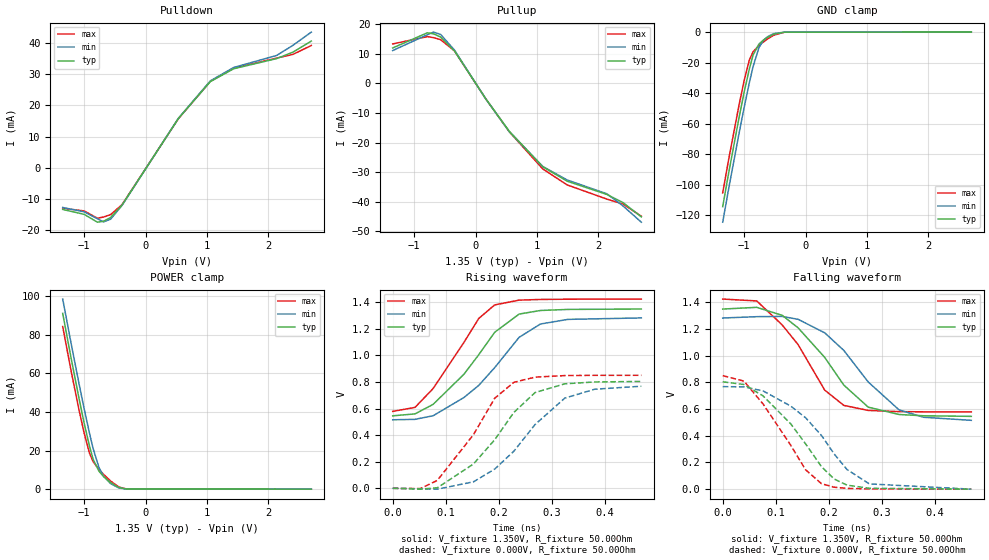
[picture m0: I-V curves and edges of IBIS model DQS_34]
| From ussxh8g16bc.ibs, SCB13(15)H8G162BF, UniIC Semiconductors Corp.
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| MODEL DQS_34 (34 Ohm Data Strobe I/O with no ODT, 800-2133Mbps)
[Model]   DQS_34
Model_type   I/O
Vinl = 545.000mV
Vinh = 805.000mV
Vmeas = 675.000mV
Vref = 675.000mV
Cref = 0.0pF
Rref = 25.000Ohm
|   typ   min   max
|C_comp   1.050pF   1.000pF   1.100pF
C_comp_pullup   0.5250pF   0.5000pF   0.5500pF
C_comp_pulldown   0.5250pF   0.5000pF   0.5500pF
[Model Spec]
| Input threshold voltage corners
Vinl   0.5450V   0.5115V   0.5825V
Vinh   0.8050V   0.7715V   0.8425V
| Measurement voltage corners
Vmeas   0.6750V   0.6415V   0.7125V
| Timing spec test load voltage corners
Vref   0.6750V   0.6415V   0.7125V
| Dynamic Overshoot Parameters from DDR3L Specification
|D_overshoot_ampl_h   0.40   NA   NA
|D_overshoot_ampl_l   0.40   NA   NA
|D_overshoot_area_h   0.11n   NA   NA
|D_overshoot_area_l   0.11n   NA   NA
[Receiver Thresholds]
|Vth   =  0.675V
|Vth_min  =  0.6615V
|Vth_max  =  0.6885V
|Vinh_ac  =  0.130V
|Vinh_dc  =  0.090V
|Vinl_ac  = -0.130V
|Vinl_dc  = -0.090V
|Tslew_ac =  5.000ns |Not specified, so set to high value
|Threshold_sensitivity = 0.50
|Reference_supply Pullup_ref
|NOTE: If using the IBISCHK 4.2.1 or older parser, Differential receiver
|threshold parameters must be commented out because the parser generates
|errors for multiple differential models.
Vcross_low   = 0.545V
Vcross_high  = 0.805V
Vdiff_ac   = 260mV
Vdiff_dc   = 180mV
Tdiffslew_ac = 10.000ns |Not specified, so set to high value
[Voltage Range]   1.3500V   1.2830V   1.4250V
[Pullup Reference]   1.3500V   1.2830V   1.4250V
| Junction Temperature (Ambient temp is 40C typ, 85C min, 0C max)
[Temperature Range]   45.0   90.0   0.0
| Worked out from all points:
|   slope of the pulldown table from 0 to 0.203 V, typ, clamps not added: 32.6 ohm
|   slope of the pullup table from 0 to 0.203 V, typ, clamps not added: 32.2 ohm
|   GND clamp passes 1 mA (typ) near -0.49 V on its own axis
|   POWER clamp passes 1 mA (typ) near -0.45 V on its own axis
|   falling waveform, V_fixture 1.350V, R_fixture 50.00Ohm: 20-80 % time 96.1ps typ, 99.3ps min, 84.6ps max; typ from 1.35 V to 0.546 V
|   rising waveform, V_fixture 1.350V, R_fixture 50.00Ohm: 20-80 % time 98.7ps typ, 106ps min, 82.4ps max; typ from 0.546 V to 1.35 V
|   rising waveform, V_fixture 0.000V, R_fixture 50.00Ohm: 20-80 % time 97.4ps typ, 105ps min, 83.3ps max; typ from 0 V to 0.805 V
|   falling waveform, V_fixture 0.000V, R_fixture 50.00Ohm: 20-80 % time 96.8ps typ, 102ps min, 82.8ps max; typ from 0.805 V to 0 V
[Pulldown]
|   Voltage   I(typ)   I(min)   I(max)
-1.35V    -13.34mA   -12.72mA   -12.97mA
-1V       -14.92mA   -14.12mA   -13.82mA
-785mV    -17.43mA   -16.34mA   -16.16mA
-685mV    -17.14mA   -17.33mA   -15.78mA
-570mV    -15.93mA   -16.47mA   -15mA
-385mV    -11.98mA   -12.09mA   -11.84mA
535mV     15.8mA     15.87mA    15.74mA
1.055V    27.62mA    27.85mA    27.66mA
1.435V    31.72mA    32.13mA    31.95mA
2.135V    34.98mA    35.99mA    35.14mA
2.4V      37.04mA    39.22mA    36.32mA
2.7V      40.59mA    43.47mA    39.18mA
[GND Clamp]
|   Voltage   I(typ)   I(min)   I(max)
-1.35V    -114.4mA   -124.6mA   -105.4mA
-1.25V    -91.71mA   -102mA     -82.85mA
-1.085V   -56.31mA   -66.65mA   -48.04mA
-1V       -39.18mA   -49.29mA   -31.62mA
-915mV    -23.97mA   -32.98mA   -18.22mA
-855mV    -15.04mA   -22.61mA   -12.89mA
-760mV    -7.865mA   -10.21mA   -8.802mA
-685mV    -5.148mA   -5.368mA   -6.421mA
-620mV    -3.44mA    -3.073mA   -4.512mA
-520mV    -1.403mA   -994uA     -2.069mA
-345mV    -90.02uA   -50.12uA   -72.43uA
2.7V      0A         0A         0A
[Pullup]
|   Voltage   I(typ)   I(min)   I(max)
-1.35V    12.01mA    11.13mA    13.37mA
-785mV    17.15mA    16.5mA     15.85mA
-685mV    16.79mA    17.38mA    15.5mA
-570mV    15.71mA    16.6mA     14.82mA
-345mV    11.06mA    11.33mA    11.04mA
165mV     -5.155mA   -5.209mA   -5.17mA
550mV     -16.21mA   -16.33mA   -16.37mA
1.095V    -28.19mA   -28.08mA   -28.92mA
1.49V     -33.05mA   -32.64mA   -34.31mA
2.14V     -37.57mA   -37.35mA   -39.14mA
2.4V      -40.28mA   -41.41mA   -40.77mA
2.7V      -45.13mA   -46.94mA   -44.93mA
[POWER Clamp]
|   Voltage   I(typ)   I(min)   I(max)
-1.35V    91.15mA    98.58mA    84.31mA
-1.21V    67.43mA    75.08mA    60.81mA
-1.085V   47.16mA    54.84mA    41.22mA
-1V       34.13mA    41.63mA    28.99mA
-915mV    22.48mA    29.16mA    18.77mA
-855mV    15.54mA    21.16mA    14.29mA
-760mV    9.343mA    11.27mA    10.24mA
-685mV    6.542mA    6.798mA    7.711mA
-570mV    3.396mA    2.887mA    4.217mA
-435mV    857.8uA    628.6uA    1.107mA
-305mV    50.49uA    49.73uA    58.69uA
2.7V      0A         0A         0A
[Ramp]
R_load = 50.00Ohm
|   typ   min   max
dV/dt_r   482.782mV/97.407ps  461.209mV/105.194ps 510.540mV/83.320ps
dV/dt_f   482.599mV/96.048ps  460.290mV/99.310ps  507.567mV/84.623ps
[Falling Waveform]
V_fixture = 1.350V
V_fixture_min = 1.283V
V_fixture_max = 1.425V
R_fixture = 50.00Ohm
|   Time   V(typ)   V(min)   V(max)
0s        1.35V      1.283V     1.425V
64ps      1.363V     1.293V     1.411V
112ps     1.303V     1.295V     1.231V
142ps     1.209V     1.273V     1.083V
192ps     987.7mV    1.172V     742.7mV
228ps     780mV      1.04V      627.9mV
274ps     614.6mV    803.1mV    590.1mV
332ps     559.6mV    594.2mV    581.3mV
378ps     550.1mV    538.9mV    579.7mV
468ps     545.7mV    515.9mV    579.1mV
[Rising Waveform]
V_fixture = 1.350V
V_fixture_min = 1.283V
V_fixture_max = 1.425V
R_fixture = 50.00Ohm
|   Time   V(typ)   V(min)   V(max)
0s        545.7mV    515.9mV    579.1mV
42ps      560.3mV    519.2mV    609.2mV
76ps      631.8mV    546.1mV    750.9mV
134ps     858.6mV    683.3mV    1.098V
162ps     1.006V     775mV      1.279V
192ps     1.175V     908.9mV    1.381V
238ps     1.312V     1.137V     1.417V
278ps     1.339V     1.237V     1.422V
330ps     1.347V     1.272V     1.424V
468ps     1.35V      1.283V     1.425V
[Rising Waveform]
V_fixture = 0.000V
V_fixture_min = 0.000V
V_fixture_max = 0.000V
R_fixture = 50.00Ohm
|   Time   V(typ)   V(min)   V(max)
0s        -23.08uV   -32.56uV   -10.33uV
52ps      -6.443mV   -4.241mV   -2.344mV
84ps      3.892mV    -6.617mV   59.32mV
152ps     182.8mV    48.66mV    403.7mV
192ps     365.6mV    144.6mV    678.1mV
228ps     571.1mV    278.9mV    797.7mV
268ps     721mV      480.1mV    837.1mV
324ps     786.8mV    679.1mV    848.7mV
380ps     800.7mV    745.9mV    850.8mV
468ps     804.6mV    768.6mV    850.9mV
[Falling Waveform]
V_fixture = 0.000V
V_fixture_min = 0.000V
V_fixture_max = 0.000V
R_fixture = 50.00Ohm
|   Time   V(typ)   V(min)   V(max)
0s        804.6mV    768.6mV    850.9mV
40ps      784.6mV    767mV      810mV
76ps      699.1mV    736.4mV    638.5mV
128ps     489.9mV    622.9mV    329.6mV
156ps     339.8mV    535.7mV    145.4mV
186ps     168.3mV    402.2mV    40.84mV
210ps     75.53mV    263mV      14.57mV
234ps     30.15mV    147.4mV    5.797mV
276ps     6.493mV    39.34mV    1.705mV
468ps     -23.08uV   -32.56uV   -10.33uV
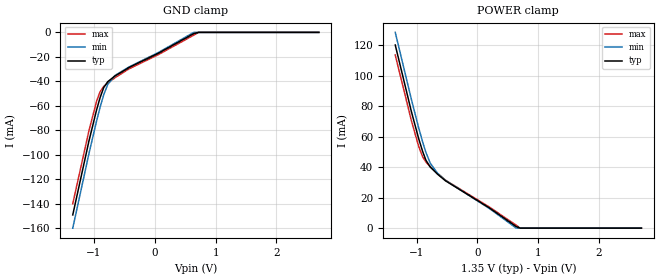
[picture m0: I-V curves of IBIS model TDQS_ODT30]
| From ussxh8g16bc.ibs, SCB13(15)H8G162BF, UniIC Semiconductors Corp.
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| MODEL TDQS_ODT30 (TDQS Terminator Model with 30ohm ODT, 800-2133Mbps)
[Model]   TDQS_ODT30
Model_type   Terminator
|   typ   min   max
|C_comp   0.989pF   0.938pF   1.051pF
C_comp_power_clamp   0.4945pF   0.4690pF   0.5255pF
C_comp_gnd_clamp   0.4945pF   0.4690pF   0.5255pF
| Note: C_comp changes when the ODT circuit is enabled.
[Voltage Range]   1.3500V   1.2830V   1.4250V
| Junction Temperature (Ambient temp is 40C typ, 85C min, 0C max)
[Temperature Range]   45.0   90.0   0.0
[GND Clamp]
|   Voltage   I(typ)   I(min)   I(max)
-1.35V    -149.3mA   -160.1mA   -140.1mA
-1.085V   -89.13mA   -99.43mA   -80.74mA
-960mV    -63.79mA   -72.88mA   -56.68mA
-900mV    -53.32mA   -61.2mA    -48.47mA
-840mV    -45.08mA   -50.91mA   -44.12mA
-775mV    -40.35mA   -42.64mA   -41.41mA
-655mV    -35.63mA   -35.25mA   -37.1mA
-425mV    -28.77mA   -28.28mA   -29.84mA
65mV      -16.87mA   -16.28mA   -18.01mA
640mV     -1.008mA   -45.78uA   -2.27mA
720mV     0A         0A         0A
2.7V      0A         0A         0A
[POWER Clamp]
|   Voltage   I(typ)   I(min)   I(max)
-1.35V    120.3mA    128.6mA    113.7mA
-1.085V   76.62mA    84.61mA    70.66mA
-965mV    58.82mA    65.95mA    53.76mA
-900mV    50.41mA    56.66mA    46.88mA
-845mV    44.56mA    49.63mA    43.37mA
-775mV    40.18mA    42.71mA    40.42mA
-655mV    35.46mA    36.07mA    35.99mA
-525mV    31.14mA    31.44mA    31.52mA
200mV     13.25mA    12.84mA    13.82mA
640mV     1.022mA    41.43uA    1.907mA
705mV     0A         0A         0A
2.7V      0A         0A         0A
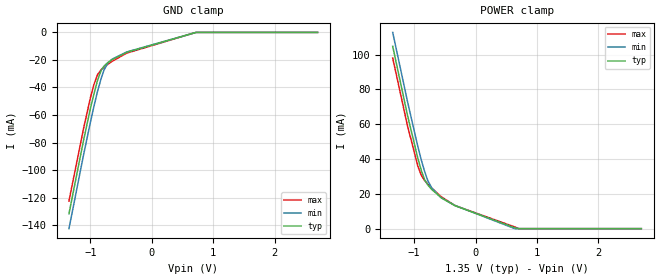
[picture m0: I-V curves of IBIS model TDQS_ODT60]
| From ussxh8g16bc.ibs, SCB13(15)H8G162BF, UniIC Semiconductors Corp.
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| MODEL TDQS_ODT60 (TDQS Terminator Model with 60ohm ODT, 800-2133Mbps)
[Model]   TDQS_ODT60
Model_type   Terminator
|   typ   min   max
|C_comp   0.962pF   0.911pF   1.017pF
C_comp_power_clamp   0.4810pF   0.4555pF   0.5085pF
C_comp_gnd_clamp   0.4810pF   0.4555pF   0.5085pF
| Note: C_comp changes when the ODT circuit is enabled.
[Voltage Range]   1.3500V   1.2830V   1.4250V
| Junction Temperature (Ambient temp is 40C typ, 85C min, 0C max)
[Temperature Range]   45.0   90.0   0.0
[GND Clamp]
|   Voltage   I(typ)   I(min)   I(max)
-1.35V    -131.8mA   -142.6mA   -122.5mA
-1.11V    -77.97mA   -88.53mA   -69.42mA
-1V       -55.11mA   -65.16mA   -47.46mA
-945mV    -45.04mA   -54.11mA   -38.1mA
-885mV    -35.01mA   -42.95mA   -30.77mA
-825mV    -27.52mA   -33.34mA   -27.09mA
-780mV    -24.5mA    -27.42mA   -25.37mA
-715mV    -21.84mA   -22.34mA   -23.18mA
-650mV    -19.84mA   -19.53mA   -21.13mA
-410mV    -14.49mA   -14.22mA   -15.06mA
720mV     0A         0A         0A
2.7V      0A         0A         0A
[POWER Clamp]
|   Voltage   I(typ)   I(min)   I(max)
-1.35V    104.7mA    112.7mA    97.98mA
-1.11V    65.25mA    73.14mA    59.19mA
-940mV    40.31mA    47.08mA    35.85mA
-885mV    33.51mA    39.51mA    30.72mA
-830mV    28.17mA    32.8mA     27.62mA
-780mV    25.15mA    27.73mA    25.67mA
-715mV    22.52mA    23.42mA    23.36mA
-560mV    17.79mA    17.7mA     18.33mA
-335mV    13.18mA    13.33mA    13.27mA
640mV     509.7uA    0A         959.2uA
705mV     0A         0A         0A
2.7V      0A         0A         0A
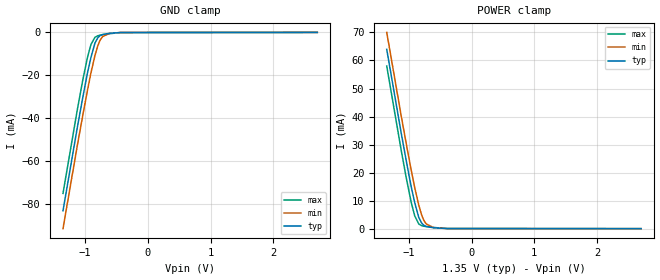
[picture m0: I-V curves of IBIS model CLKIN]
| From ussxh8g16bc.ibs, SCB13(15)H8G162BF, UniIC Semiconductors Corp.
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| MODEL CLKIN (Clock Input Model, 800-2133Mbps)
[Model]   CLKIN
Model_type   Input
Vinl = 550.000mV
Vinh = 800.000mV
|   typ   min   max
|C_comp   0.650pF   0.610pF   0.690pF
C_comp_power_clamp   0.3250pF   0.3050pF   0.3450pF
C_comp_gnd_clamp   0.3250pF   0.3050pF   0.3450pF
[Model Spec]
| Input threshold voltage corners
Vinl   0.5500V   0.5165V   0.5875V
Vinh   0.8000V   0.7665V   0.8375V
| Dynamic Overshoot Parameters from DDR3L Specification
|D_overshoot_ampl_h   0.40   NA   NA
|D_overshoot_ampl_l   0.40   NA   NA
|D_overshoot_area_h   0.11n   NA   NA
|D_overshoot_area_l   0.11n   NA   NA
[Receiver Thresholds]
|Vth   =  0.675V
|Vth_min  =  0.6615V
|Vth_max  =  0.6885V
|Vinh_ac  =  0.125V
|Vinh_dc  =  0.090V
|Vinl_ac  = -0.125V
|Vinl_dc  = -0.090V
|Tslew_ac =  5.000ns |Not specified, so set to high value
|Threshold_sensitivity = 0.50
|Reference_supply Power_clamp_ref
|NOTE: If using the IBISCHK 4.2.1 or older parser, Differential receiver
|threshold parameters must be commented out because the parser generates
|errors for multiple differential models.
Vcross_low   = 0.550V
Vcross_high  = 0.800V
Vdiff_ac   = 250mV
Vdiff_dc   = 180mV
Tdiffslew_ac = 10.000ns |Not specified, so set to high value
[Voltage Range]   1.3500V   1.2830V   1.4250V
[POWER Clamp Reference]   1.3500V   1.2830V   1.4250V
| Junction Temperature (Ambient temp is 40C typ, 85C min, 0C max)
[Temperature Range]   45.0   90.0   0.0
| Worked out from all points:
|   GND clamp passes 1 mA (typ) near -0.72 V on its own axis
|   POWER clamp passes 1 mA (typ) near -0.74 V on its own axis
[GND Clamp]
|   Voltage   I(typ)   I(min)   I(max)
-1.35V    -82.97mA   -91.28mA   -74.88mA
-1.12V    -43.93mA   -52.35mA   -35.67mA
-1.035V   -30.3mA    -38.57mA   -22.2mA
-960mV    -18.84mA   -26.9mA    -11.62mA
-905mV    -11.64mA   -18.85mA   -5.649mA
-840mV    -4.895mA   -10.65mA   -2.263mA
-795mV    -2.462mA   -6.171mA   -1.56mA
-760mV    -1.514mA   -3.65mA    -1.299mA
-720mV    -987.9uA   -1.99mA    -1.084mA
-610mV    -437.6uA   -460.5uA   -598.1uA
-430mV    -50.87uA   -28.69uA   -92.05uA
2.7V      0A         0A         0A
[POWER Clamp]
|   Voltage   I(typ)   I(min)   I(max)
-1.35V    63.96mA    70.02mA    58mA
-1.12V    34.14mA    40.31mA    28mA
-1.035V   23.71mA    29.78mA    17.64mA
-960mV    14.91mA    20.86mA    9.395mA
-905mV    9.336mA    14.7mA     4.597mA
-840mV    4.026mA    8.406mA    1.674mA
-795mV    2.026mA    4.946mA    1.063mA
-760mV    1.218mA    2.981mA    868.9uA
-720mV    762.4uA    1.667mA    730.8uA
-605mV    331.8uA    382.9uA    423.4uA
-385mV    37.76uA    23.51uA    48.75uA
2.7V      0A         0A         0A
